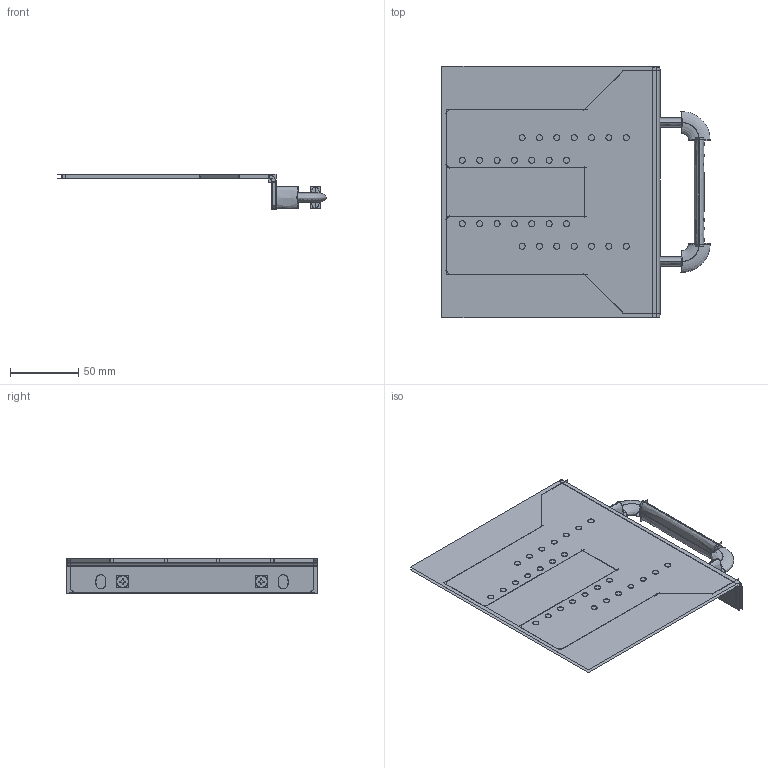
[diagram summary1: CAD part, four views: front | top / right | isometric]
IGES file: header records copied from the file, then geometry measured from it (millimetres).
Start section:  PTC IGES file: assy_rack_mount_left_pxie-1078_asm.igs
Global section: file name: assy_rack_mount_left_pxie-1078_asm.igs; native system: Pro/ENGINEER by Parametric Technology Corporation; preprocessor: 2010230; author: talbott; organization: Unknown; date: 20111115.104419; units: inch
Bounding box: 196.12 x 184.12 x 25.64 mm (x, y, z)
Surface area: 127973.3 mm2 (no closed solid volume)
Topology: 0 solids, 0 shells, 354 faces, 4799 edges, 6185 vertices
Faces by surface type: bspline 182, revolution 172
